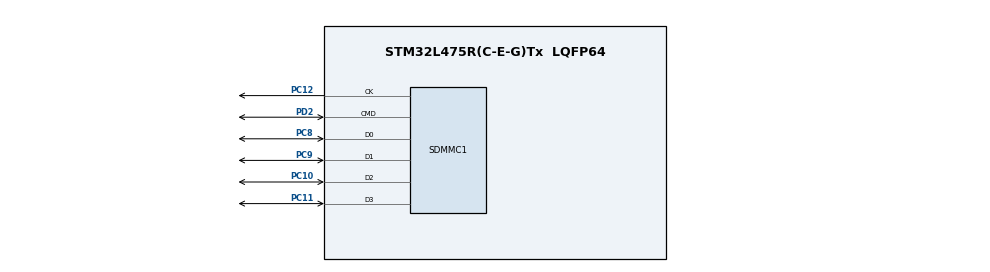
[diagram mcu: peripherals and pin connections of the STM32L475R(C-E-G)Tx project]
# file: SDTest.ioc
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FATFS._MAX_SS=4096
Mcu.Family=STM32L4
Mcu.Name=STM32L475R(C-E-G)Tx
Mcu.Package=LQFP64
NVIC.PriorityGroup=NVIC_PRIORITYGROUP_4
NVIC.SDMMC1_IRQn=true\:0\:0\:false\:false\:true\:true\:true
PC10.GPIO_PuPd=GPIO_NOPULL
PC10.Mode=SD_4_bits_Wide_bus
PC10.Signal=SDMMC1_D2
PC11.GPIO_PuPd=GPIO_NOPULL
PC11.Mode=SD_4_bits_Wide_bus
PC11.Signal=SDMMC1_D3
PC12.Mode=SD_4_bits_Wide_bus
PC12.Signal=SDMMC1_CK
PC8.GPIO_PuPd=GPIO_NOPULL
PC8.Mode=SD_4_bits_Wide_bus
PC8.Signal=SDMMC1_D0
PC9.GPIO_PuPd=GPIO_NOPULL
PC9.Mode=SD_4_bits_Wide_bus
PC9.Signal=SDMMC1_D1
PD2.GPIO_PuPd=GPIO_NOPULL
PD2.Mode=SD_4_bits_Wide_bus
PD2.Signal=SDMMC1_CMD
ProjectManager.HeapSize=0x200
ProjectManager.StackSize=0x400
ProjectManager.TargetToolchain=TrueSTUDIO
RCC.ADCFreq_Value=128000000
RCC.AHBFreq_Value=32000000
RCC.APB1Freq_Value=32000000
RCC.APB1TimFreq_Value=32000000
RCC.APB2Freq_Value=32000000
RCC.APB2TimFreq_Value=32000000
RCC.CK48CLockSelection=RCC_USBCLKSOURCE_MSI
RCC.CortexFreq_Value=32000000
RCC.HCLKFreq_Value=32000000
RCC.HSE_VALUE=8000000
RCC.HSI_VALUE=16000000
RCC.LSE_VALUE=32768
RCC.MSIClockRange=RCC_MSIRANGE_10
RCC.MSI_VALUE=32000000
RCC.SYSCLKFreq_VALUE=32000000
RCC.USBFreq_Value=32000000
RCC.VCOOutputFreq_Value=256000000
VP_FATFS_VS_SDIO.Mode=SDIO
board=custom

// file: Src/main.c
/* USER CODE BEGIN Header */
/**
  ******************************************************************************
  * @file           : main.c
  * @brief          : Main program body
  ******************************************************************************
  * @attention
  *
  * <h2><center>&copy; Copyright (c) 2019 STMicroelectronics.
  * All rights reserved.</center></h2>
  *
  * This software component is licensed by ST under Ultimate Liberty license
  * SLA0044, the "License"; You may not use this file except in compliance with
  * the License. You may obtain a copy of the License at:
  *                             www.st.com/SLA0044
  *
  ******************************************************************************
  */
/* USER CODE END Header */

#include "main.h"
#include "fatfs.h"

SD_HandleTypeDef hsd1;

/* USER CODE BEGIN PV */
/* Private variables ---------------------------------------------------------*/

/* USER CODE END PV */

void SystemClock_Config(void);
static void MX_GPIO_Init(void);
static void MX_SDMMC1_SD_Init(void);
/* USER CODE BEGIN PFP */
/* Private function prototypes -----------------------------------------------*/

/* USER CODE END PFP */

/* USER CODE BEGIN 0 */
FATFS SDFatFs;  /* File system object for SD card logical drive */

FIL MyFile;     /* File object */

char SD_Path[4];  /* SD logical drive path */
/* USER CODE END 0 */

int __attribute__((optimize("O0"))) main(void)
{

  /* MCU Configuration--------------------------------------------------------*/

  /* Reset of all peripherals, Initializes the Flash interface and the Systick. */
  HAL_Init();

  /* Configure the system clock */
  SystemClock_Config();

  /* Initialize all configured peripherals */
  MX_GPIO_Init();
  MX_SDMMC1_SD_Init();
  MX_FATFS_Init();
  /* USER CODE BEGIN 2 */
//  BSP_SD_Init();
//  HAL_Delay(200);
//  MX_FATFS_Init();

  /* USER CODE END 2 */

  /* Infinite loop */
  /* USER CODE BEGIN WHILE */
  FRESULT res = f_mount(&SDFatFs, (TCHAR const*)SD_Path, 1);
	 if(res != FR_OK)
	    Error_Handler();
	  else
	  {
		  uint8_t arr[] = {0, 1, 2};
		  uint8_t arrrd[20];
		  uint8_t* bw;
		  res = f_open(&MyFile, "adr.txt", FA_READ|FA_WRITE);
		  res = f_read(&MyFile, arrrd, 10, bw);
		  res = f_write(&MyFile, arr, 3, bw);
//          if(f_open(&MyFile, "adr.txt", FA_READ) != FR_OK)
//                    Error_Handler();
//            else
//            {
//                          f_close(&MyFile);
//            }
	  }
  while (1)
  {
	  asm("nop");
    /* USER CODE END WHILE */

  }
}

void SystemClock_Config(void)
{
  RCC_OscInitTypeDef RCC_OscInitStruct = {0};
  RCC_ClkInitTypeDef RCC_ClkInitStruct = {0};
  RCC_PeriphCLKInitTypeDef PeriphClkInit = {0};

  /** Initializes the CPU, AHB and APB busses clocks
  */
  RCC_OscInitStruct.OscillatorType = RCC_OSCILLATORTYPE_MSI;
  RCC_OscInitStruct.MSIState = RCC_MSI_ON;
  RCC_OscInitStruct.MSICalibrationValue = 0;
  RCC_OscInitStruct.MSIClockRange = RCC_MSIRANGE_6;
  RCC_OscInitStruct.PLL.PLLState = RCC_PLL_ON;
  RCC_OscInitStruct.PLL.PLLSource = RCC_PLLSOURCE_MSI;
  RCC_OscInitStruct.PLL.PLLM = 1;
  RCC_OscInitStruct.PLL.PLLN = 40;
  RCC_OscInitStruct.PLL.PLLP = RCC_PLLP_DIV7;
  RCC_OscInitStruct.PLL.PLLQ = RCC_PLLQ_DIV2;
  RCC_OscInitStruct.PLL.PLLR = RCC_PLLR_DIV2;
  if (HAL_RCC_OscConfig(&RCC_OscInitStruct) != HAL_OK)
  {
    Error_Handler();
  }
  /** Initializes the CPU, AHB and APB busses clocks
  */
  RCC_ClkInitStruct.ClockType = RCC_CLOCKTYPE_HCLK|RCC_CLOCKTYPE_SYSCLK
                              |RCC_CLOCKTYPE_PCLK1|RCC_CLOCKTYPE_PCLK2;
  RCC_ClkInitStruct.SYSCLKSource = RCC_SYSCLKSOURCE_PLLCLK;
  RCC_ClkInitStruct.AHBCLKDivider = RCC_SYSCLK_DIV1;
  RCC_ClkInitStruct.APB1CLKDivider = RCC_HCLK_DIV1;
  RCC_ClkInitStruct.APB2CLKDivider = RCC_HCLK_DIV1;

  if (HAL_RCC_ClockConfig(&RCC_ClkInitStruct, FLASH_LATENCY_4) != HAL_OK)
  {
    Error_Handler();
  }
  PeriphClkInit.PeriphClockSelection = RCC_PERIPHCLK_SDMMC1;
  PeriphClkInit.Sdmmc1ClockSelection = RCC_SDMMC1CLKSOURCE_PLLSAI1;
  PeriphClkInit.PLLSAI1.PLLSAI1Source = RCC_PLLSOURCE_MSI;
  PeriphClkInit.PLLSAI1.PLLSAI1M = 1;
  PeriphClkInit.PLLSAI1.PLLSAI1N = 16;
  PeriphClkInit.PLLSAI1.PLLSAI1P = RCC_PLLP_DIV7;
  PeriphClkInit.PLLSAI1.PLLSAI1Q = RCC_PLLQ_DIV2;
  PeriphClkInit.PLLSAI1.PLLSAI1R = RCC_PLLR_DIV2;
  PeriphClkInit.PLLSAI1.PLLSAI1ClockOut = RCC_PLLSAI1_48M2CLK;
  if (HAL_RCCEx_PeriphCLKConfig(&PeriphClkInit) != HAL_OK)
  {
    Error_Handler();
  }
  /** Configure the main internal regulator output voltage
  */
  if (HAL_PWREx_ControlVoltageScaling(PWR_REGULATOR_VOLTAGE_SCALE1) != HAL_OK)
  {
    Error_Handler();
  }
}

static void MX_SDMMC1_SD_Init(void)
{

  hsd1.Instance = SDMMC1;
  hsd1.Init.ClockEdge = SDMMC_CLOCK_EDGE_RISING;
  hsd1.Init.ClockBypass = SDMMC_CLOCK_BYPASS_DISABLE;
  hsd1.Init.ClockPowerSave = SDMMC_CLOCK_POWER_SAVE_DISABLE;
  hsd1.Init.BusWide = SDMMC_BUS_WIDE_1B;
  hsd1.Init.HardwareFlowControl = SDMMC_HARDWARE_FLOW_CONTROL_DISABLE;
  hsd1.Init.ClockDiv = 0;

}

static void MX_GPIO_Init(void)
{

  /* GPIO Ports Clock Enable */
  __HAL_RCC_GPIOC_CLK_ENABLE();
  __HAL_RCC_GPIOD_CLK_ENABLE();

}

void Error_Handler(void)
{
  while(1)
  {
  }
}

/************************ (C) COPYRIGHT STMicroelectronics *****END OF FILE****/
